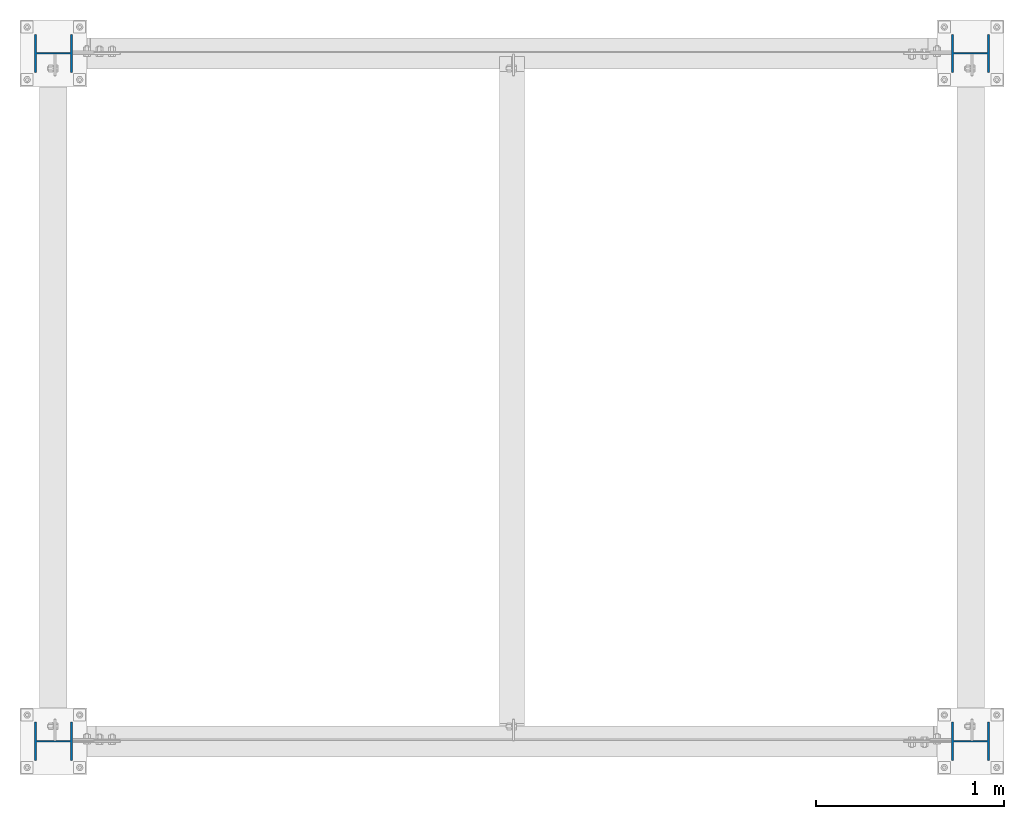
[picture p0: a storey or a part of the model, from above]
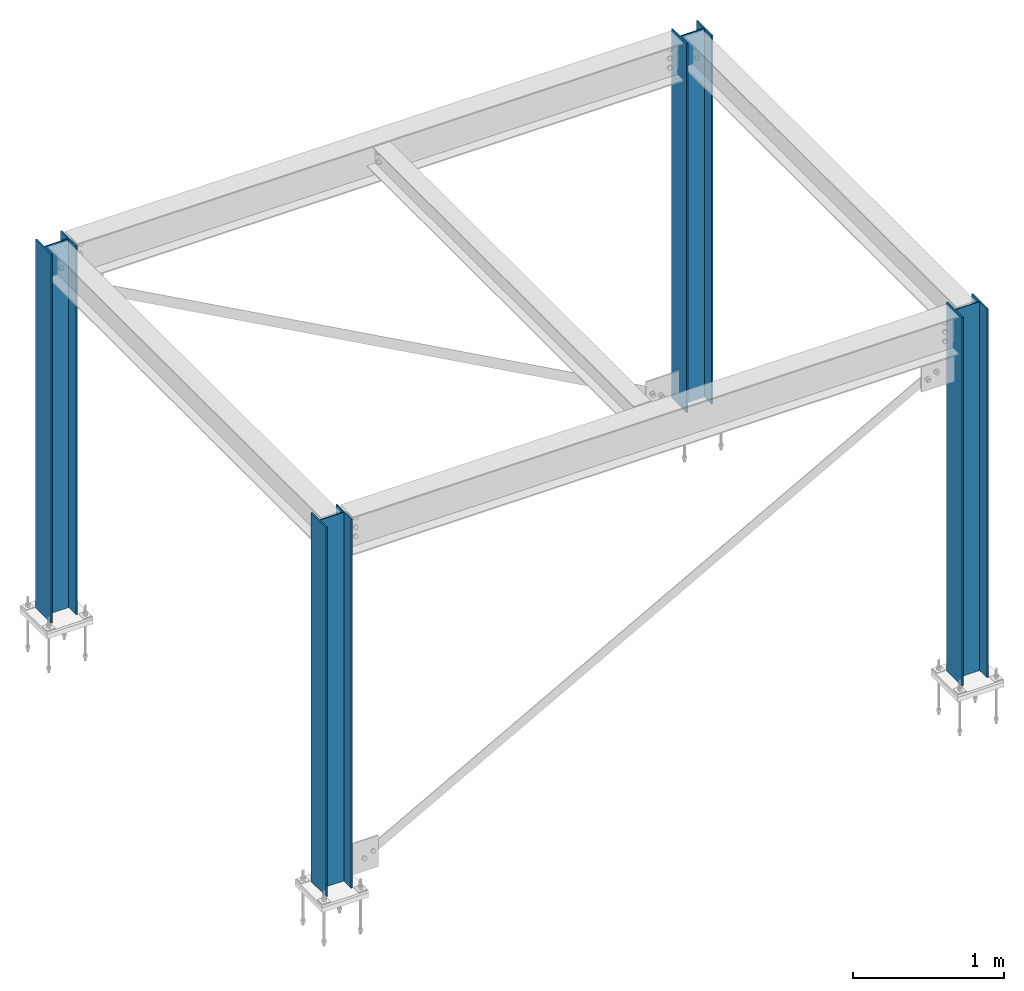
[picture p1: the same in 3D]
Properties of the parts of a building model (IFC4)

# File
Description: ViewDefinition [ReferenceView_V1.2], ExchangeRequirement [Structural], Option[Flat wide beams as plates:Off], Option[Location by:Global], Option[Locations from Organizer:Off], Option[Layer:Name], Option[Object coloring:ByObjectClass], Option[Export All:On], Option[Export Pours:Off]
File name: US_SAMPLE_PLATFORM_IFC4.ifc
Time: 2026-10-29T01:29:41
Author: STRUCTOMAT
Organization: STRUCTOMAT
Written by: IFC Export version May 9 2026
Made in: STRUCTOMAT
Authorization: IFC4 model

# IfcBuildingStorey, Unknown
In: Unknown
Elevation: 0 mm

# IfcBeam (5)
In: Unknown
Material: A992
Name | Description
2 x BEAM | W12X26
2 x BEAM | W10X22
BEAM | W8X18

# IfcColumn (68)
In: Unknown
Name | Description | Material
4 x COLUMN | W8X31 | A992
32 x ANCHOR NUT | NUT_M21.167 | A563
16 x LEVELING NUT | NUT_M21.167 | A563
16 x ANCHOR ROD | ROD19.05 | F1554-36

# IfcGrid (2)
In: Unknown
PredefinedType: RECTANGULAR
Name
T.O.CONC.
T.O.S.

# IfcMechanicalFastener (18)
In: Unknown
Name | Material
14 x BOLT 3/4"DIA A325 1"3/4 | A325N
4 x A307 | A307

# IfcMember (2)
In: Unknown
Description: L3X3X1/4; Material: A36

# IfcPlate (34)
In: Unknown
Material: A36
Name | Description
4 x GUSSET PLATE | PL9.525
10 x SHEAR TAB | PL9.525
4 x BASEPLATE | PL19.05
16 x PLATE WASHER | PL6.35

# IfcSlab (4)
In: Unknown
Description: PL38.1; Material: GROUT

# IfcVoidingFeature (34)
In: Unknown
PredefinedType: HOLE
Name | Description
16 x BEAM | D39.7
16 x BEAM | D20.637
2 x BEAM | PL203.20*50.80
